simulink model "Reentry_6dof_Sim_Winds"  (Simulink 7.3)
settings: Solver=ode45  StartTime=0.0  StopTime=1901.8  FixedStep=0.01
InitFcn:
  | init
StopFcn:
  | pl
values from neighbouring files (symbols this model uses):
  d2r = pi/180    (= 0.0174532925199)    [init.m]    (also in pl.m; robust.m)
  h0 = 250000.0    (= 250000)    [init.m]
  mass = 528.0    (= 528)    [init.m]
  q = 12    [Lateral_FCS.m]    (also in Pitch_FCS.m = 26)
  r2d = 180/pi    (= 57.2957795131)    [init.m]    (also in pl.m; robust.m)
  sp = 15    [init.m]
  x0 = [0 0 -2 -2 0 0 18 0 0 0]'*d2r    [init.m]
  x_cg = -17.04    [init.m]
  x_ref = -16.2    [init.m]
  y_cg = 0    [init.m]
  z_cg = -2.03    [init.m]
  z_ref = -2.1    [init.m]
undefined symbols (not defined in the file or in its folder): Cl, Cld1, Cld2, Cld3, Cld4, Cld5, Cld6, Cld7, Cm, Cmd1, Cmd2, Cmd3, Cmd4, Cmd5, Cmd6, Cmd7, Cn, Cnd1, Cnd2, Cnd3, Cnd4, Cnd5, Cnd6, Cnd7, Continuous, CX, CXd1, CXd2, CXd3, CXd4, CXd5, CXd6, CXd7, CY, CYd1, CYd2, CYd3, CYd4, CYd5, CYd6, CYd7, CZ, CZd1, CZd2, CZd3, CZd4, CZd5, CZd6, CZd7, Dryden, F, ft, HDBK, km, KmixM0p4, Lateral_FCS, Light, MIL, Pitch_FCS, r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
libraries: aerolibasang x3, aerolibwind2 x3, aerolib6dof2 x1, aerolibconvert2 x1, aerolibatmos2 x1, aerolibgravity2 x1, aerolibadyn x1
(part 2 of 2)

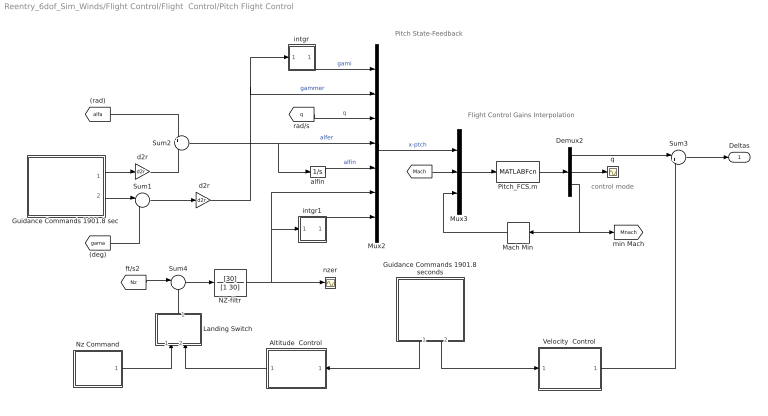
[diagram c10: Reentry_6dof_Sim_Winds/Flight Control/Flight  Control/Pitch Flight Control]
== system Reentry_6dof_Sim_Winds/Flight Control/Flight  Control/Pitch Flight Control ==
  note: Pitch State-Feedback
  note: Flight Control Gains Interpolation
  note: control mode
  " d2r" : Gain  Gain=d2r  ParameterDataType=fixdt(1, 16)  ParameterScaling=2^0  OutDataType=fixdt(1, 16)  OutScaling=2^0
  Altitude  Control : Subsystem
  Demux2 : Demux  Outputs=[7,1,1]
  Guidance Commands 1901.8 seconds : Subsystem  Tag=STV Subsys  LoadFcn=sigbuilder_block('load');  StartFcn=sigbuilder_block('start');  StopFcn=sigbuilder_block('stop');  ClipboardFcn=sigbuilder_block('clipboard');
  Guidance Commands 1901.8 sec : Subsystem  Tag=STV Subsys  LoadFcn=sigbuilder_block('load');  StartFcn=sigbuilder_block('start');  StopFcn=sigbuilder_block('stop');  ClipboardFcn=sigbuilder_block('clipboard');
  Landing Switch : Subsystem
  Mach Min : Memory  X0=30
  Mux2 : Mux  Inputs=7
  Mux3 : Mux  Inputs=[7, 1,1]
  NZ-filtr : TransferFcn  Numerator=[30]  Denominator=[1 30]
  Nz Command : Subsystem  Tag=STV Subsys  LoadFcn=sigbuilder_block('load');  StartFcn=sigbuilder_block('start');  StopFcn=sigbuilder_block('stop');  ClipboardFcn=sigbuilder_block('clipboard');
  Pitch_FCS.m : MATLABFcn  MATLABFcn=Pitch_FCS( u(1:7), u(8), u(9) )  OutputDimensions=9
  Sum1 : Sum  Inputs=|-+  OutDataType=fixdt(1, 16)  OutScaling=2^0
  Sum2 : Sum  Inputs=+|-  OutDataType=fixdt(1, 16)  OutScaling=2^0
  Sum3 : Sum  Inputs=|++  OutDataType=fixdt(1, 16)  OutScaling=2^0
  Sum4 : Sum  Inputs=|+-  OutDataType=fixdt(1, 16)  OutScaling=2^0
  Velocity  Control : Subsystem
  alfin : Integrator
  d2r : Gain  Gain=d2r  ParameterDataType=fixdt(1, 16)  ParameterScaling=2^0  OutDataType=fixdt(1, 16)  OutScaling=2^0
  intgr : Subsystem
  intgr1 : Subsystem
  nzer : Scope
  q : Scope
  Deltas : Outport
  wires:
  [q] -> Mux2/3  "q"
  intgr/1(gi) -> Mux2/1  "gami"
  alfin/1 -> Mux2/5  "alfin"
  Nz Command/1(Nz_cmd) -> Landing Switch/1(In1)
  [Nz] -> Sum4/1
  intgr1/1(nzi) -> Mux2/7
  NZ-filtr/1 -> Mux2/6, intgr1/1(nze), nzer/1
  Sum4/1 -> NZ-filtr/1
  Pitch_FCS.m/1 -> Demux2/1
  Demux2/1 -> Sum3/1
  Demux2/2 -> q/1
  Mux3/1 -> Pitch_FCS.m/1
  Mux2/1 -> Mux3/1  "x-ptch"
  [Mach] -> Mux3/2
  Guidance Commands 1901.8 sec/1(Alpha_cmd) -> d2r/1
  Sum2/1 -> Mux2/4, alfin/1  "alfer"
  Guidance Commands 1901.8 sec/2(Gamma_cmd) -> Sum1/1
  [gama] -> Sum1/2
  Sum1/1 -> " d2r"/1
  d2r/1 -> Sum2/2
  " d2r"/1 -> Mux2/2, intgr/1(ge)  "gammer"
  [alfa] -> Sum2/1
  Landing Switch/1(out) -> Sum4/2
  Altitude  Control/1(Nz_cmd) -> Landing Switch/2(In2)
  Guidance Commands 1901.8 seconds/1(Altitude) -> Altitude  Control/1(href)
  Velocity  Control/1(deltas) -> Sum3/2
  Sum3/1 -> Deltas/1
  Guidance Commands 1901.8 seconds/2(Velocity) -> Velocity  Control/1(Vel)
  Mach Min/1 -> Mux3/3
  Demux2/3 -> Mach Min/1, [Mnach]

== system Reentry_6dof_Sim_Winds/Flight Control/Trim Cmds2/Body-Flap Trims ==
  Demux : Demux  Tag=STV Demux
  FromWs : FromWorkspace  Tag=STV FromWs  VariableName=tuvar  SampleTime=0  SigBuilderData=DataTag8  VnvData=DataTag9
  Up-Left BF : Outport  Tag=STV Outport
  Up Right BF : Outport  Tag=STV Outport  Port=2
  Lo-Left BF : Outport  Tag=STV Outport  Port=3
  Lo-Right BF : Outport  Tag=STV Outport  Port=4
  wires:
  Demux/4 -> Lo-Right BF/1
  Demux/3 -> Lo-Left BF/1
  Demux/2 -> Up Right BF/1
  Demux/1 -> Up-Left BF/1
  FromWs/1 -> Demux/1

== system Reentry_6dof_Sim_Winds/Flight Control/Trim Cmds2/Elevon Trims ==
  Demux : Demux  Tag=STV Demux  Outputs=2
  FromWs : FromWorkspace  Tag=STV FromWs  VariableName=tuvar  SampleTime=0  SigBuilderData=DataTag10  VnvData=DataTag11
  Left Elev : Outport  Tag=STV Outport
  Right Elev : Outport  Tag=STV Outport  Port=2
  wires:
  Demux/2 -> Right Elev/1
  Demux/1 -> Left Elev/1
  FromWs/1 -> Demux/1

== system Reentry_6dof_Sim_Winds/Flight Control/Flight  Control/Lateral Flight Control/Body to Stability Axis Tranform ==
  note: Body to Stability Axes Transformation
  p_b : Inport  OutDataType=sfix(16)  OutScaling=2^0
  r_b : Inport  Port=2  OutDataType=sfix(16)  OutScaling=2^0
  Cos : Subsystem
  "Cos " : Subsystem
  Sin : Subsystem
  "Sin " : Subsystem
  Sum1 : Sum  Inputs=+|+  OutDataType=sfix(16)  OutScaling=2^0
  Sum2 : Sum  Inputs=+|-  OutDataType=sfix(16)  OutScaling=2^0
  p_s : Outport  OutDataType=sfix(16)  OutScaling=2^0
  r_s : Outport  Port=2  OutDataType=sfix(16)  OutScaling=2^0
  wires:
  Sum1/1 -> p_s/1
  Sum2/1 -> r_s/1
  p_b/1 -> Cos/2(in), "Sin "/2(in)
  r_b/1 -> Sin/2(in), "Cos "/2(in)
  Sin/1(sa) -> Sum1/2
  "Cos "/1(ca) -> Sum2/1
  "Sin "/1(sa) -> Sum2/2
  Cos/1(ca) -> Sum1/1
  [alfa] -> Cos/1(alf), Sin/1(alf), "Cos "/1(alf), "Sin "/1(alf)

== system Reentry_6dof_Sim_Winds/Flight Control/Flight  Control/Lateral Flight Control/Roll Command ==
  Demux : Demux  Tag=STV Demux  Outputs=1
  FromWs : FromWorkspace  Tag=STV FromWs  VariableName=tuvar  SampleTime=0  SigBuilderData=DataTag0  VnvData=DataTag1
  Phi_cmd : Outport  Tag=STV Outport
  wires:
  FromWs/1 -> Demux/1
  Demux/1 -> Phi_cmd/1

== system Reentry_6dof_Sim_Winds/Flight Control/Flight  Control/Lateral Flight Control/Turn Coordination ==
  note: Turn Coordination Rff = (g/V0)*sin(phi)
  phi : Inport
  Divide : Product  Inputs=**/  OutDataType=fixdt(1, 16)  OutScaling=2^-10
  g : Constant  Value=-32.174  OutDataType=fixdt(1, 16)  OutScaling=2^0
  sin : Trigonometry
  Rff : Outport
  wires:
  [V0] -> Divide/3
  sin/1 -> Divide/1
  phi/1 -> sin/1
  Divide/1 -> Rff/1
  g/1 -> Divide/2

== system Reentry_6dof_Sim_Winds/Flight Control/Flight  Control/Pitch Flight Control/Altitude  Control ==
  note: Altitude Control Loop
  note: Final Flare (open-loop)
  note: Automatically raises the vehicle nose up, 50 (ft) before hitting the ground
  href : Inport
  Anti-Phugoid2 : TransferFcn  Numerator="[5.08  1]"  Denominator=[9 1]
  Filtr  30/(s+30) : Subsystem
  Flare : TransferFcn  Numerator="[1  0]"  Denominator=[3 1]
  Flare_cmd : Constant  Value=10  OutDataType=fixdt(1, 16)  OutScaling=2^0
  Kff : Gain  Gain=4  ParameterDataType=sfix(16)  ParameterScaling=2^0  OutDataType=sfix(16)  OutScaling=2^0
  "Nz_cmd " : Sum  OutDataType=sfix(16)  OutScaling=2^0
  Sum1 : Sum  Inputs=-+|  OutDataType=fixdt(1, 16)  OutScaling=2^0
  Sum2 : Sum  Inputs=|+-  OutDataType=fixdt(1, 16)  OutScaling=2^0
  Switch : Switch  Criteria=u2 > Threshold  Threshold=50  OutDataType=fixdt(1, 16)  OutScaling=2^0
  gr : Ground
  kh=0.0159 : Gain  Gain=0.0159  ParameterDataType=sfix(16)  ParameterScaling=2^0  OutDataType=sfix(16)  OutScaling=2^0
  khd=0.0174 : Gain  Gain=0.0174  ParameterDataType=sfix(16)  ParameterScaling=2^0  OutDataType=sfix(16)  OutScaling=2^0
  Nz_cmd : Outport
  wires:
  [hdot] -> khd=0.0174/1
  kh=0.0159/1 -> "Nz_cmd "/2
  [h] -> Sum1/2, Switch/2
  Sum1/1 -> kh=0.0159/1
  khd=0.0174/1 -> "Nz_cmd "/1
  Switch/1 -> Flare/1
  Flare/1 -> Kff/1
  gr/1 -> Switch/1
  Flare_cmd/1 -> Switch/3
  "Nz_cmd "/1 -> Filtr  30/(s+30)/1(hi)
  Kff/1 -> Sum2/2
  href/1 -> Sum1/1
  Filtr  30/(s+30)/1(ho) -> Anti-Phugoid2/1
  Sum2/1 -> Nz_cmd/1
  Anti-Phugoid2/1 -> Sum2/1

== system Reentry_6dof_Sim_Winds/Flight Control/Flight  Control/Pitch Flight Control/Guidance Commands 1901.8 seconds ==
  Demux : Demux  Tag=STV Demux  Outputs=2
  FromWs : FromWorkspace  Tag=STV FromWs  VariableName=tuvar  SampleTime=0  SigBuilderData=DataTag2  VnvData=DataTag3
  Altitude : Outport  Tag=STV Outport
  Velocity : Outport  Tag=STV Outport  Port=2
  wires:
  Demux/2 -> Velocity/1
  Demux/1 -> Altitude/1
  FromWs/1 -> Demux/1

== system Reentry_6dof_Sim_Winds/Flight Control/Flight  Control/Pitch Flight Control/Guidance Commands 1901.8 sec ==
  Demux : Demux  Tag=STV Demux  Outputs=2
  FromWs : FromWorkspace  Tag=STV FromWs  VariableName=tuvar  SampleTime=0  SigBuilderData=DataTag4  VnvData=DataTag5
  Alpha_cmd : Outport  Tag=STV Outport
  Gamma_cmd : Outport  Tag=STV Outport  Port=2
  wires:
  Demux/2 -> Gamma_cmd/1
  Demux/1 -> Alpha_cmd/1
  FromWs/1 -> Demux/1

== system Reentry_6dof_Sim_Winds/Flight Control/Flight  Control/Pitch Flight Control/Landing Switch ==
  In1 : Inport
  In2 : Inport  Port=2
  -1 : Gain  Gain=-1  ParameterDataType=sfix(16)  ParameterScaling=2^0  OutDataType=sfix(16)  OutScaling=2^0
  Sum4 : Sum  Inputs=+|+  OutDataType=fixdt(1, 16)  OutScaling=2^0
  Switch : Switch  Threshold=0.48  OutDataType=fixdt(1, 16)  OutScaling=2^0
  gr : Ground
  out : Outport
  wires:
  In1/1 -> -1/1
  -1/1 -> Sum4/1
  [Mach] -> Switch/2
  In2/1 -> Switch/3
  Sum4/1 -> out/1
  Switch/1 -> Sum4/2
  gr/1 -> Switch/1

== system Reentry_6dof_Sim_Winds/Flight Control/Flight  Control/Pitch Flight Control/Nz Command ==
  Demux : Demux  Tag=STV Demux  Outputs=1
  FromWs : FromWorkspace  Tag=STV FromWs  VariableName=tuvar  SampleTime=0  SigBuilderData=DataTag6  VnvData=DataTag7
  Nz_cmd : Outport  Tag=STV Outport
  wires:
  Demux/1 -> Nz_cmd/1
  FromWs/1 -> Demux/1

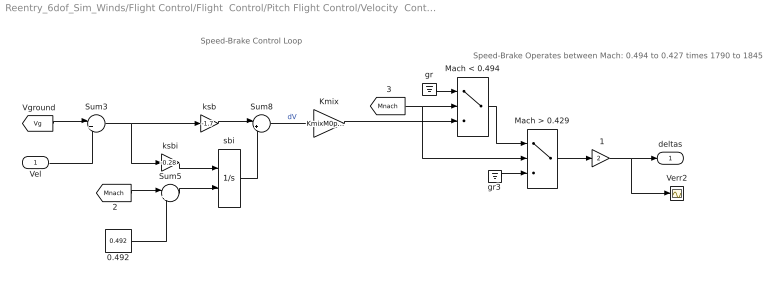
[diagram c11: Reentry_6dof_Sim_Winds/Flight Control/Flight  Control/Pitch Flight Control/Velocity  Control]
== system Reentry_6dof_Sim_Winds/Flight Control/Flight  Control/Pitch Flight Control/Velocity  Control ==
  note: Speed-Brake Control Loop
  note: Speed-Brake Operates between Mach: 0.494 to 0.427 times 1790 to 1845
  Vel : Inport
  " 1" : Gain  Gain=2  ParameterDataType=sfix(16)  ParameterScaling=2^0  OutDataType=sfix(16)  OutScaling=2^0
  0.492 : Constant  Value=0.492  OutDataType=fixdt(1, 16)  OutScaling=2^0
  Kmix : Gain  Gain=KmixM0p4(:,4)  Multiplication=Matrix(K*u)  ParameterDataType=sfix(16)  ParameterScaling=2^0  OutDataType=sfix(16)  OutScaling=2^0
  Mach < 0.494 : Switch  Threshold=0.492  OutDataType=fixdt(1, 16)  OutScaling=2^0
  Mach > 0.429 : Switch  Threshold=0.4326  OutDataType=fixdt(1, 16)  OutScaling=2^0
  Sum3 : Sum  Inputs=|+-  OutDataType=fixdt(1, 16)  OutScaling=2^0
  Sum5 : Sum  Inputs=|+-  OutDataType=fixdt(1, 16)  OutScaling=2^0
  Sum8 : Sum  Inputs=|++  OutDataType=sfix(16)  OutScaling=2^0
  Verr2 : Scope
  gr : Ground
  gr3 : Ground
  ksb : Gain  Gain=-1.7  ParameterDataType=sfix(16)  ParameterScaling=2^0  OutDataType=sfix(16)  OutScaling=2^0
  ksbi : Gain  Gain=-0.28  ParameterDataType=sfix(16)  ParameterScaling=2^0  OutDataType=sfix(16)  OutScaling=2^0
  sbi : Integrator  ExternalReset=falling  UpperSaturationLimit=20  LowerSaturationLimit=-20
  deltas : Outport
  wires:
  Sum3/1 -> ksbi/1, ksb/1
  ksb/1 -> Sum8/1
  ksbi/1 -> sbi/1
  Sum8/1 -> Kmix/1  "dV"
  [Vg] -> Sum3/1
  [Mnach] -> Sum5/1
  0.492/1 -> Sum5/2
  Sum5/1 -> sbi/2
  sbi/1 -> Sum8/2
  Vel/1 -> Sum3/2
  [Mnach] -> Mach < 0.494/2, Mach > 0.429/2
  " 1"/1 -> deltas/1, Verr2/1
  Mach > 0.429/1 -> " 1"/1
  gr/1 -> Mach < 0.494/1
  gr3/1 -> Mach > 0.429/3
  Mach < 0.494/1 -> Mach > 0.429/1
  Kmix/1 -> Mach < 0.494/3

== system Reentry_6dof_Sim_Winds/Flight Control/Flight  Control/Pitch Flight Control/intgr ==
  ge : Inport
  Switch : Switch  Threshold=4  OutDataType=fixdt(1, 16)  OutScaling=2^0
  gamin : Integrator  UpperSaturationLimit=20  LowerSaturationLimit=-20
  gamint : Scope
  gamint1 : Scope
  gr : Ground
  gi : Outport
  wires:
  Switch/1 -> gamin/1
  gr/1 -> Switch/1
  [Mach] -> Switch/2
  ge/1 -> Switch/3, gamint1/1
  gamin/1 -> gi/1, gamint/1  "gamin"

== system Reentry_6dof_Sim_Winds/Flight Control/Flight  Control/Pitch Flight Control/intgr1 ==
  nze : Inport
  Switch : Switch  Threshold=17  OutDataType=fixdt(1, 16)  OutScaling=2^0
  gamin : Integrator  UpperSaturationLimit=20  LowerSaturationLimit=-20
  gr : Ground
  nzeint : Scope
  nzi : Outport
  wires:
  Switch/1 -> gamin/1
  gr/1 -> Switch/1
  [Mach] -> Switch/2
  nze/1 -> Switch/3
  gamin/1 -> nzi/1, nzeint/1  "gamin"

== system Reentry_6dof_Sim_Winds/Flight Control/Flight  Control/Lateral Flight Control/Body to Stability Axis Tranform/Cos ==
  alf : Inport
  in : Inport  Port=2  OutDataType=sfix(16)  OutScaling=2^0
  Product : Product  OutDataType=fixdt(1, 16)  OutScaling=2^0
  cos : Trigonometry  Operator=cos
  ca : Outport
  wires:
  cos/1 -> Product/1
  in/1 -> Product/2
  alf/1 -> cos/1
  Product/1 -> ca/1

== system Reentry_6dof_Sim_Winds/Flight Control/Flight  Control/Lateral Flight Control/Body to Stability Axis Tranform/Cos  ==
  alf : Inport
  in : Inport  Port=2  OutDataType=sfix(16)  OutScaling=2^0
  Product : Product  OutDataType=fixdt(1, 16)  OutScaling=2^0
  cos : Trigonometry  Operator=cos
  ca : Outport
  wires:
  cos/1 -> Product/1
  in/1 -> Product/2
  alf/1 -> cos/1
  Product/1 -> ca/1

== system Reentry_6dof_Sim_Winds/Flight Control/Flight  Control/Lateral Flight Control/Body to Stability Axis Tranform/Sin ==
  alf : Inport
  in : Inport  Port=2  OutDataType=sfix(16)  OutScaling=2^0
  Product : Product  OutDataType=fixdt(1, 16)  OutScaling=2^0
  sin : Trigonometry
  sa : Outport
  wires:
  sin/1 -> Product/1
  in/1 -> Product/2
  alf/1 -> sin/1
  Product/1 -> sa/1

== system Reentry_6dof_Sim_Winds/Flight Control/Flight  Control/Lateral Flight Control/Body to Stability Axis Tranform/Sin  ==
  alf : Inport
  in : Inport  Port=2  OutDataType=sfix(16)  OutScaling=2^0
  Product : Product  OutDataType=fixdt(1, 16)  OutScaling=2^0
  sin : Trigonometry
  sa : Outport
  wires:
  sin/1 -> Product/1
  in/1 -> Product/2
  alf/1 -> sin/1
  Product/1 -> sa/1

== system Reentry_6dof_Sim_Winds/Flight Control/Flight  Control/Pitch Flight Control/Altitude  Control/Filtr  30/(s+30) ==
  hi : Inport
  0.5 : Constant  Value=0.49  OutDataType=fixdt(1, 16)  OutScaling=2^0
  30 : Gain  Gain=30  ParameterDataType=sfix(16)  ParameterScaling=2^0  OutDataType=sfix(16)  OutScaling=2^0
  Sum1 : Sum  Inputs=|+-  OutDataType=fixdt(1, 16)  OutScaling=2^0
  Sum5 : Sum  Inputs=|+-  OutDataType=fixdt(1, 16)  OutScaling=2^0
  hi1 : Integrator  ExternalReset=falling  UpperSaturationLimit=20  LowerSaturationLimit=-20
  ho : Outport
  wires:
  [Mach] -> Sum1/1
  hi1/1 -> ho/1, Sum5/2
  Sum5/1 -> 30/1
  hi/1 -> Sum5/1
  30/1 -> hi1/1
  Sum1/1 -> hi1/2
  0.5/1 -> Sum1/2
